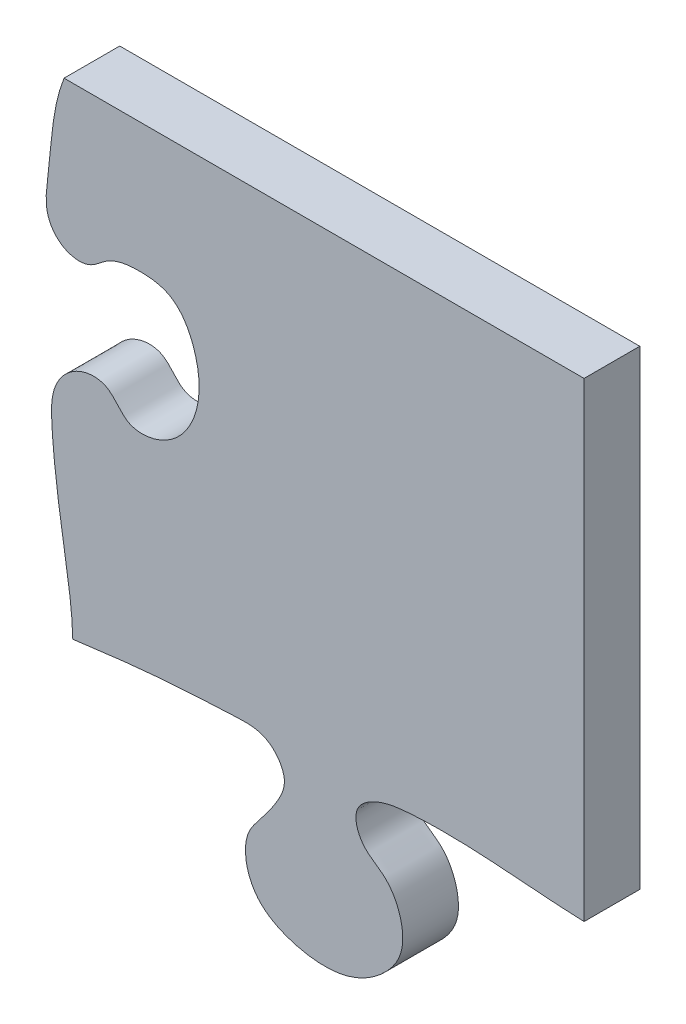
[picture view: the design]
ISO-10303-21;
HEADER;
FILE_DESCRIPTION(('STEP AP214'),'2;1');
FILE_NAME('part.step','',(''),(''),'','','');
FILE_SCHEMA(('AUTOMOTIVE_DESIGN { 1 0 10303 214 1 1 1 1 }'));
ENDSEC;
DATA;
#1=APPLICATION_CONTEXT('core data for automotive mechanical design processes');
#2=APPLICATION_PROTOCOL_DEFINITION('international standard','automotive_design',2000,#1);
#3=PRODUCT_CONTEXT('',#1,'mechanical');
#4=PRODUCT('Part','Part','',(#3));
#5=PRODUCT_RELATED_PRODUCT_CATEGORY('part','',(#4));
#6=PRODUCT_DEFINITION_FORMATION('','',#4);
#7=PRODUCT_DEFINITION_CONTEXT('part definition',#1,'design');
#8=PRODUCT_DEFINITION('design','',#6,#7);
#9=PRODUCT_DEFINITION_SHAPE('','',#8);
#10=(LENGTH_UNIT() NAMED_UNIT(*) SI_UNIT(.MILLI.,.METRE.));
#11=(NAMED_UNIT(*) PLANE_ANGLE_UNIT() SI_UNIT($,.RADIAN.));
#12=(NAMED_UNIT(*) SI_UNIT($,.STERADIAN.) SOLID_ANGLE_UNIT());
#13=UNCERTAINTY_MEASURE_WITH_UNIT(LENGTH_MEASURE(1.E-05),#10,'distance_accuracy_value','');
#14=(GEOMETRIC_REPRESENTATION_CONTEXT(3) GLOBAL_UNCERTAINTY_ASSIGNED_CONTEXT((#13)) GLOBAL_UNIT_ASSIGNED_CONTEXT((#10,
#11,#12)) REPRESENTATION_CONTEXT('',''));
#15=CARTESIAN_POINT('',(0.,0.,0.));
#16=DIRECTION('',(0.,0.,1.));
#17=DIRECTION('',(1.,0.,0.));
#18=AXIS2_PLACEMENT_3D('',#15,#16,#17);
#19=CARTESIAN_POINT('',(325.257058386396,356.,-0.00999999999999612));
#20=CARTESIAN_POINT('',(320.961162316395,345.029410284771,-0.00999999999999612));
#21=CARTESIAN_POINT('',(320.821863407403,330.111228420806,-0.00999999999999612));
#22=CARTESIAN_POINT('',(317.746642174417,310.708405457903,-0.00999999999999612));
#23=CARTESIAN_POINT('',(324.80874526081,302.068845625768,-0.00999999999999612));
#24=CARTESIAN_POINT('',(334.47949844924,301.092198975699,-0.00999999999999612));
#25=CARTESIAN_POINT('',(341.199385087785,308.405018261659,-0.00999999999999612));
#26=CARTESIAN_POINT('',(351.88918877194,310.104343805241,-0.00999999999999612));
#27=CARTESIAN_POINT('',(365.477229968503,308.551893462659,-0.00999999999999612));
#28=CARTESIAN_POINT('',(373.973100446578,293.452904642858,-0.00999999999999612));
#29=CARTESIAN_POINT('',(374.68177629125,275.222888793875,-0.00999999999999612));
#30=CARTESIAN_POINT('',(363.969524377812,260.217712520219,-0.00999999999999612));
#31=CARTESIAN_POINT('',(347.560929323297,258.00994019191,-0.00999999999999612));
#32=CARTESIAN_POINT('',(341.667769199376,269.318092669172,-0.00999999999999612));
#33=CARTESIAN_POINT('',(329.050646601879,268.591464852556,-0.00999999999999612));
#34=CARTESIAN_POINT('',(320.333215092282,258.695380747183,-0.00999999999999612));
#35=CARTESIAN_POINT('',(321.071783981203,237.536716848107,-0.00999999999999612));
#36=CARTESIAN_POINT('',(324.445641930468,214.63289279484,-0.00999999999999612));
#37=CARTESIAN_POINT('',(329.382935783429,185.164436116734,-0.00999999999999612));
#38=CARTESIAN_POINT('',(327.148862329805,151.381238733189,-0.00999999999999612));
#39=CARTESIAN_POINT('',(325.104399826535,122.782989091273,-0.00999999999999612));
#40=CARTESIAN_POINT('',(327.870971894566,95.9027200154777,-0.00999999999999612));
#41=CARTESIAN_POINT('',(342.142457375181,93.3383677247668,-0.00999999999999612));
#42=CARTESIAN_POINT('',(347.900573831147,101.981576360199,-0.00999999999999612));
#43=CARTESIAN_POINT('',(356.834615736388,107.765098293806,-0.00999999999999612));
#44=CARTESIAN_POINT('',(369.379527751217,108.600772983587,-0.00999999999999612));
#45=CARTESIAN_POINT('',(380.120269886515,95.9775166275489,-0.00999999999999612));
#46=CARTESIAN_POINT('',(380.578851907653,78.7451628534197,-0.00999999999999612));
#47=CARTESIAN_POINT('',(375.610818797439,61.7248962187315,-0.00999999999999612));
#48=CARTESIAN_POINT('',(363.715824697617,52.8157722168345,-0.00999999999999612));
#49=CARTESIAN_POINT('',(349.85984979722,55.1705340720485,-0.00999999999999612));
#50=CARTESIAN_POINT('',(346.945856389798,64.810819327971,-0.00999999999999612));
#51=CARTESIAN_POINT('',(338.689797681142,70.9897723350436,-0.00999999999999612));
#52=CARTESIAN_POINT('',(330.580353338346,62.4728514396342,-0.00999999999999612));
#53=CARTESIAN_POINT('',(328.928359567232,48.4436203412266,-0.00999999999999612));
#54=CARTESIAN_POINT('',(329.318852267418,30.6791591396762,-0.00999999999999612));
#55=CARTESIAN_POINT('',(330.266196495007,6.75725364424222,-0.00999999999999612));
#56=CARTESIAN_POINT('',(328.413221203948,-22.8156731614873,-0.00999999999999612));
#57=CARTESIAN_POINT('',(325.957403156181,-47.4645191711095,-0.00999999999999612));
#58=CARTESIAN_POINT('',(324.284943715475,-71.7282942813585,-0.00999999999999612));
#59=CARTESIAN_POINT('',(336.158184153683,-74.5800053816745,-0.00999999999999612));
#60=CARTESIAN_POINT('',(345.605596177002,-70.2479425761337,-0.00999999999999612));
#61=CARTESIAN_POINT('',(352.349142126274,-60.6528291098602,-0.00999999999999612));
#62=CARTESIAN_POINT('',(364.054661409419,-61.084248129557,-0.00999999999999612));
#63=CARTESIAN_POINT('',(376.894401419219,-65.7171784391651,-0.00999999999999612));
#64=CARTESIAN_POINT('',(383.833690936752,-81.7570856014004,-0.00999999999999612));
#65=CARTESIAN_POINT('',(380.385627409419,-99.5380411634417,-0.00999999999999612));
#66=CARTESIAN_POINT('',(369.163029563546,-108.064440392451,-0.00999999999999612));
#67=CARTESIAN_POINT('',(355.487733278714,-112.894616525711,-0.00999999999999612));
#68=CARTESIAN_POINT('',(345.56890588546,-106.804716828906,-0.00999999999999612));
#69=CARTESIAN_POINT('',(337.864154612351,-99.6791187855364,-0.00999999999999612));
#70=CARTESIAN_POINT('',(325.333875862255,-101.340144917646,-0.00999999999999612));
#71=CARTESIAN_POINT('',(326.442256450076,-127.027418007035,-0.00999999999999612));
#72=CARTESIAN_POINT('',(328.990782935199,-147.650339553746,-0.00999999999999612));
#73=CARTESIAN_POINT('',(331.889209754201,-175.720931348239,-0.00999999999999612));
#74=CARTESIAN_POINT('',(333.49389611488,-200.043501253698,-0.00999999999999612));
#75=CARTESIAN_POINT('',(333.062418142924,-222.75850264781,-0.00999999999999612));
#76=CARTESIAN_POINT('',(334.041200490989,-241.335918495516,-0.00999999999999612));
#77=CARTESIAN_POINT('',(324.292862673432,-248.82670983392,-0.00999999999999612));
#78=CARTESIAN_POINT('',(313.862264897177,-249.831348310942,-0.00999999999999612));
#79=CARTESIAN_POINT('',(308.055191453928,-242.821422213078,-0.00999999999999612));
#80=CARTESIAN_POINT('',(300.480173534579,-235.015509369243,-0.00999999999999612));
#81=CARTESIAN_POINT('',(285.021810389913,-234.387092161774,-0.00999999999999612));
#82=CARTESIAN_POINT('',(274.179995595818,-248.432983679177,-0.00999999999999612));
#83=CARTESIAN_POINT('',(270.871780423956,-265.971502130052,-0.00999999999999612));
#84=CARTESIAN_POINT('',(274.212392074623,-284.032454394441,-0.00999999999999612));
#85=CARTESIAN_POINT('',(287.225269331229,-295.05235393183,-0.00999999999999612));
#86=CARTESIAN_POINT('',(300.809811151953,-292.931473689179,-0.00999999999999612));
#87=CARTESIAN_POINT('',(307.364923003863,-284.321305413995,-0.00999999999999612));
#88=CARTESIAN_POINT('',(317.634904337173,-281.646810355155,-0.00999999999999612));
#89=CARTESIAN_POINT('',(335.194502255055,-286.515768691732,-0.00999999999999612));
#90=CARTESIAN_POINT('',(329.900008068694,-321.054322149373,-0.00999999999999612));
#91=CARTESIAN_POINT('',(330.939416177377,-339.80390498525,-0.00999999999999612));
#92=CARTESIAN_POINT('',(328.124742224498,-356.,-0.00999999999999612));
#93=B_SPLINE_CURVE_WITH_KNOTS('',3,(#19,#20,#21,#22,#23,#24,#25,#26,#27,#28,#29,#30,#31,#32,#33,
#34,#35,#36,#37,#38,#39,#40,#41,#42,#43,#44,#45,#46,#47,#48,#49,#50,#51,#52,#53,#54,#55,#56,#57,
#58,#59,#60,#61,#62,#63,#64,#65,#66,#67,#68,#69,#70,#71,#72,#73,#74,#75,#76,#77,#78,#79,#80,#81,
#82,#83,#84,#85,#86,#87,#88,#89,#90,#91,#92),.UNSPECIFIED.,.F.,.F.,(4,1,1,1,1,1,1,1,1,1,1,1,1,1,
1,1,1,1,1,1,1,1,1,1,1,1,1,1,1,1,1,1,1,1,1,1,1,1,1,1,1,1,1,1,1,1,1,1,1,1,1,1,1,1,1,1,1,1,1,1,1,1,
1,1,1,1,1,1,1,1,1,4),(0.,0.0294359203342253,0.0410015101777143,0.0482578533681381,
0.056156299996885,0.0628725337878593,0.0726761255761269,0.0834491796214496,0.0961628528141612,
0.113582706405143,0.1292026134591,0.140393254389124,0.149299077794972,0.1578234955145,
0.168702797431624,0.18034067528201,0.211171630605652,0.230177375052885,0.258218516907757,
0.297936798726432,0.310855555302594,0.319545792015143,0.327782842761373,0.335750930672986,
0.347377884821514,0.35651553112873,0.375682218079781,0.389966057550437,0.401463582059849,
0.411615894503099,0.420595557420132,0.426581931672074,0.43417370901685,0.444880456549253,
0.464136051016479,0.480140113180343,0.507902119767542,0.539252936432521,0.552990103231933,
0.558383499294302,0.567729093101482,0.578921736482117,0.586248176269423,0.596305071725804,
0.613504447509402,0.626237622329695,0.64117705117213,0.647978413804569,0.662971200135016,
0.667795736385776,0.675224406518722,0.689293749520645,0.721613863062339,0.73643728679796,
0.762019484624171,0.785031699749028,0.797726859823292,0.806664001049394,0.814473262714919,
0.822386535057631,0.828765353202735,0.842978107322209,0.855573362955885,0.871677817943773,
0.889062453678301,0.900888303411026,0.912516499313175,0.920249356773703,0.928039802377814,
0.939164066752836,0.961164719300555,1.),.UNSPECIFIED.);
#94=DIRECTION('',(0.,0.,1.));
#95=VECTOR('',#94,1.);
#96=SURFACE_OF_LINEAR_EXTRUSION('',#93,#95);
#97=DIRECTION('',(0.,0.,1.));
#98=VECTOR('',#97,1.);
#99=CARTESIAN_POINT('',(328.393413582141,183.083092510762,-0.00999999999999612));
#100=LINE('',#99,#98);
#101=CARTESIAN_POINT('',(328.393413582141,183.083092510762,20.));
#102=VERTEX_POINT('',#101);
#103=CARTESIAN_POINT('',(328.393413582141,183.083092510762,0.));
#104=VERTEX_POINT('',#103);
#105=EDGE_CURVE('E95',#102,#104,#100,.F.);
#106=ORIENTED_EDGE('',*,*,#105,.F.);
#107=CARTESIAN_POINT('',(325.257058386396,356.,20.));
#108=CARTESIAN_POINT('',(320.961162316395,345.029410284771,20.));
#109=CARTESIAN_POINT('',(320.821863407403,330.111228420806,20.));
#110=CARTESIAN_POINT('',(317.746642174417,310.708405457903,20.));
#111=CARTESIAN_POINT('',(324.80874526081,302.068845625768,20.));
#112=CARTESIAN_POINT('',(334.47949844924,301.092198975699,20.));
#113=CARTESIAN_POINT('',(341.199385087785,308.405018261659,20.));
#114=CARTESIAN_POINT('',(351.88918877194,310.104343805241,20.));
#115=CARTESIAN_POINT('',(365.477229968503,308.551893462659,20.));
#116=CARTESIAN_POINT('',(373.973100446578,293.452904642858,20.));
#117=CARTESIAN_POINT('',(374.68177629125,275.222888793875,20.));
#118=CARTESIAN_POINT('',(363.969524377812,260.217712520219,20.));
#119=CARTESIAN_POINT('',(347.560929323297,258.00994019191,20.));
#120=CARTESIAN_POINT('',(341.667769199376,269.318092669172,20.));
#121=CARTESIAN_POINT('',(329.050646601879,268.591464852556,20.));
#122=CARTESIAN_POINT('',(320.333215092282,258.695380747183,20.));
#123=CARTESIAN_POINT('',(321.071783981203,237.536716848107,20.));
#124=CARTESIAN_POINT('',(324.445641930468,214.63289279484,20.));
#125=CARTESIAN_POINT('',(329.382935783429,185.164436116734,20.));
#126=CARTESIAN_POINT('',(327.148862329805,151.381238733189,20.));
#127=CARTESIAN_POINT('',(325.104399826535,122.782989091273,20.));
#128=CARTESIAN_POINT('',(327.870971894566,95.9027200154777,20.));
#129=CARTESIAN_POINT('',(342.142457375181,93.3383677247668,20.));
#130=CARTESIAN_POINT('',(347.900573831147,101.981576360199,20.));
#131=CARTESIAN_POINT('',(356.834615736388,107.765098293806,20.));
#132=CARTESIAN_POINT('',(369.379527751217,108.600772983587,20.));
#133=CARTESIAN_POINT('',(380.120269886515,95.9775166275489,20.));
#134=CARTESIAN_POINT('',(380.578851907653,78.7451628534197,20.));
#135=CARTESIAN_POINT('',(375.610818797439,61.7248962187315,20.));
#136=CARTESIAN_POINT('',(363.715824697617,52.8157722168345,20.));
#137=CARTESIAN_POINT('',(349.85984979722,55.1705340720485,20.));
#138=CARTESIAN_POINT('',(346.945856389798,64.810819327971,20.));
#139=CARTESIAN_POINT('',(338.689797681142,70.9897723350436,20.));
#140=CARTESIAN_POINT('',(330.580353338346,62.4728514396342,20.));
#141=CARTESIAN_POINT('',(328.928359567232,48.4436203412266,20.));
#142=CARTESIAN_POINT('',(329.318852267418,30.6791591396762,20.));
#143=CARTESIAN_POINT('',(330.266196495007,6.75725364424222,20.));
#144=CARTESIAN_POINT('',(328.413221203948,-22.8156731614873,20.));
#145=CARTESIAN_POINT('',(325.957403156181,-47.4645191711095,20.));
#146=CARTESIAN_POINT('',(324.284943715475,-71.7282942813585,20.));
#147=CARTESIAN_POINT('',(336.158184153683,-74.5800053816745,20.));
#148=CARTESIAN_POINT('',(345.605596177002,-70.2479425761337,20.));
#149=CARTESIAN_POINT('',(352.349142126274,-60.6528291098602,20.));
#150=CARTESIAN_POINT('',(364.054661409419,-61.084248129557,20.));
#151=CARTESIAN_POINT('',(376.894401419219,-65.7171784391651,20.));
#152=CARTESIAN_POINT('',(383.833690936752,-81.7570856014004,20.));
#153=CARTESIAN_POINT('',(380.385627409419,-99.5380411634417,20.));
#154=CARTESIAN_POINT('',(369.163029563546,-108.064440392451,20.));
#155=CARTESIAN_POINT('',(355.487733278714,-112.894616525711,20.));
#156=CARTESIAN_POINT('',(345.56890588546,-106.804716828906,20.));
#157=CARTESIAN_POINT('',(337.864154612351,-99.6791187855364,20.));
#158=CARTESIAN_POINT('',(325.333875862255,-101.340144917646,20.));
#159=CARTESIAN_POINT('',(326.442256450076,-127.027418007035,20.));
#160=CARTESIAN_POINT('',(328.990782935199,-147.650339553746,20.));
#161=CARTESIAN_POINT('',(331.889209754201,-175.720931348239,20.));
#162=CARTESIAN_POINT('',(333.49389611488,-200.043501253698,20.));
#163=CARTESIAN_POINT('',(333.062418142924,-222.75850264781,20.));
#164=CARTESIAN_POINT('',(334.041200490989,-241.335918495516,20.));
#165=CARTESIAN_POINT('',(324.292862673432,-248.82670983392,20.));
#166=CARTESIAN_POINT('',(313.862264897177,-249.831348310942,20.));
#167=CARTESIAN_POINT('',(308.055191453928,-242.821422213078,20.));
#168=CARTESIAN_POINT('',(300.480173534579,-235.015509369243,20.));
#169=CARTESIAN_POINT('',(285.021810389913,-234.387092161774,20.));
#170=CARTESIAN_POINT('',(274.179995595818,-248.432983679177,20.));
#171=CARTESIAN_POINT('',(270.871780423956,-265.971502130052,20.));
#172=CARTESIAN_POINT('',(274.212392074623,-284.032454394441,20.));
#173=CARTESIAN_POINT('',(287.225269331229,-295.05235393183,20.));
#174=CARTESIAN_POINT('',(300.809811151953,-292.931473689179,20.));
#175=CARTESIAN_POINT('',(307.364923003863,-284.321305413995,20.));
#176=CARTESIAN_POINT('',(317.634904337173,-281.646810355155,20.));
#177=CARTESIAN_POINT('',(335.194502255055,-286.515768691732,20.));
#178=CARTESIAN_POINT('',(329.900008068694,-321.054322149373,20.));
#179=CARTESIAN_POINT('',(330.939416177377,-339.80390498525,20.));
#180=CARTESIAN_POINT('',(328.124742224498,-356.,20.));
#181=B_SPLINE_CURVE_WITH_KNOTS('',3,(#107,#108,#109,#110,#111,#112,#113,#114,#115,#116,#117,
#118,#119,#120,#121,#122,#123,#124,#125,#126,#127,#128,#129,#130,#131,#132,#133,#134,#135,#136,
#137,#138,#139,#140,#141,#142,#143,#144,#145,#146,#147,#148,#149,#150,#151,#152,#153,#154,#155,
#156,#157,#158,#159,#160,#161,#162,#163,#164,#165,#166,#167,#168,#169,#170,#171,#172,#173,#174,
#175,#176,#177,#178,#179,#180),.UNSPECIFIED.,.F.,.F.,(4,1,1,1,1,1,1,1,1,1,1,1,1,1,1,1,1,1,1,1,1,
1,1,1,1,1,1,1,1,1,1,1,1,1,1,1,1,1,1,1,1,1,1,1,1,1,1,1,1,1,1,1,1,1,1,1,1,1,1,1,1,1,1,1,1,1,1,1,1,
1,1,4),(0.,0.0294359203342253,0.0410015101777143,0.0482578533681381,0.056156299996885,
0.0628725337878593,0.0726761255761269,0.0834491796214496,0.0961628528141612,0.113582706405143,
0.1292026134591,0.140393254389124,0.149299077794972,0.1578234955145,0.168702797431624,
0.18034067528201,0.211171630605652,0.230177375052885,0.258218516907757,0.297936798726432,
0.310855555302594,0.319545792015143,0.327782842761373,0.335750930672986,0.347377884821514,
0.35651553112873,0.375682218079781,0.389966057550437,0.401463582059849,0.411615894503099,
0.420595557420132,0.426581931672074,0.43417370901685,0.444880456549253,0.464136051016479,
0.480140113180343,0.507902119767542,0.539252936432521,0.552990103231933,0.558383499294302,
0.567729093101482,0.578921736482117,0.586248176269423,0.596305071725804,0.613504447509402,
0.626237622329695,0.64117705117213,0.647978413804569,0.662971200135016,0.667795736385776,
0.675224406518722,0.689293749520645,0.721613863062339,0.73643728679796,0.762019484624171,
0.785031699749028,0.797726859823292,0.806664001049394,0.814473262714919,0.822386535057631,
0.828765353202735,0.842978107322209,0.855573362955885,0.871677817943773,0.889062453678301,
0.900888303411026,0.912516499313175,0.920249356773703,0.928039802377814,0.939164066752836,
0.961164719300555,1.),.UNSPECIFIED.);
#182=CARTESIAN_POINT('',(325.257058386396,356.,20.));
#183=VERTEX_POINT('',#182);
#184=EDGE_CURVE('E94',#183,#102,#181,.T.);
#185=ORIENTED_EDGE('',*,*,#184,.F.);
#186=DIRECTION('',(0.,0.,1.));
#187=VECTOR('',#186,1.);
#188=CARTESIAN_POINT('',(325.257058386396,356.,-0.00999999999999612));
#189=LINE('',#188,#187);
#190=CARTESIAN_POINT('',(325.257058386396,356.,0.));
#191=VERTEX_POINT('',#190);
#192=EDGE_CURVE('E82',#183,#191,#189,.F.);
#193=ORIENTED_EDGE('',*,*,#192,.T.);
#194=CARTESIAN_POINT('',(325.257058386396,356.,0.));
#195=CARTESIAN_POINT('',(320.961162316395,345.029410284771,0.));
#196=CARTESIAN_POINT('',(320.821863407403,330.111228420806,0.));
#197=CARTESIAN_POINT('',(317.746642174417,310.708405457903,0.));
#198=CARTESIAN_POINT('',(324.80874526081,302.068845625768,0.));
#199=CARTESIAN_POINT('',(334.47949844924,301.092198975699,0.));
#200=CARTESIAN_POINT('',(341.199385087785,308.405018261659,0.));
#201=CARTESIAN_POINT('',(351.88918877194,310.104343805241,0.));
#202=CARTESIAN_POINT('',(365.477229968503,308.551893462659,0.));
#203=CARTESIAN_POINT('',(373.973100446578,293.452904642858,0.));
#204=CARTESIAN_POINT('',(374.68177629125,275.222888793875,0.));
#205=CARTESIAN_POINT('',(363.969524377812,260.217712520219,0.));
#206=CARTESIAN_POINT('',(347.560929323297,258.00994019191,0.));
#207=CARTESIAN_POINT('',(341.667769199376,269.318092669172,0.));
#208=CARTESIAN_POINT('',(329.050646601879,268.591464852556,0.));
#209=CARTESIAN_POINT('',(320.333215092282,258.695380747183,0.));
#210=CARTESIAN_POINT('',(321.071783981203,237.536716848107,0.));
#211=CARTESIAN_POINT('',(324.445641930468,214.63289279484,0.));
#212=CARTESIAN_POINT('',(329.382935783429,185.164436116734,0.));
#213=CARTESIAN_POINT('',(327.148862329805,151.381238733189,0.));
#214=CARTESIAN_POINT('',(325.104399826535,122.782989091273,0.));
#215=CARTESIAN_POINT('',(327.870971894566,95.9027200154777,0.));
#216=CARTESIAN_POINT('',(342.142457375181,93.3383677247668,0.));
#217=CARTESIAN_POINT('',(347.900573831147,101.981576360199,0.));
#218=CARTESIAN_POINT('',(356.834615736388,107.765098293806,0.));
#219=CARTESIAN_POINT('',(369.379527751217,108.600772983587,0.));
#220=CARTESIAN_POINT('',(380.120269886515,95.9775166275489,0.));
#221=CARTESIAN_POINT('',(380.578851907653,78.7451628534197,0.));
#222=CARTESIAN_POINT('',(375.610818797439,61.7248962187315,0.));
#223=CARTESIAN_POINT('',(363.715824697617,52.8157722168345,0.));
#224=CARTESIAN_POINT('',(349.85984979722,55.1705340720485,0.));
#225=CARTESIAN_POINT('',(346.945856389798,64.810819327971,0.));
#226=CARTESIAN_POINT('',(338.689797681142,70.9897723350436,0.));
#227=CARTESIAN_POINT('',(330.580353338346,62.4728514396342,0.));
#228=CARTESIAN_POINT('',(328.928359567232,48.4436203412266,0.));
#229=CARTESIAN_POINT('',(329.318852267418,30.6791591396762,0.));
#230=CARTESIAN_POINT('',(330.266196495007,6.75725364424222,0.));
#231=CARTESIAN_POINT('',(328.413221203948,-22.8156731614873,0.));
#232=CARTESIAN_POINT('',(325.957403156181,-47.4645191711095,0.));
#233=CARTESIAN_POINT('',(324.284943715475,-71.7282942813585,0.));
#234=CARTESIAN_POINT('',(336.158184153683,-74.5800053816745,0.));
#235=CARTESIAN_POINT('',(345.605596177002,-70.2479425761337,0.));
#236=CARTESIAN_POINT('',(352.349142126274,-60.6528291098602,0.));
#237=CARTESIAN_POINT('',(364.054661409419,-61.084248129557,0.));
#238=CARTESIAN_POINT('',(376.894401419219,-65.7171784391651,0.));
#239=CARTESIAN_POINT('',(383.833690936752,-81.7570856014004,0.));
#240=CARTESIAN_POINT('',(380.385627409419,-99.5380411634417,0.));
#241=CARTESIAN_POINT('',(369.163029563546,-108.064440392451,0.));
#242=CARTESIAN_POINT('',(355.487733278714,-112.894616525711,0.));
#243=CARTESIAN_POINT('',(345.56890588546,-106.804716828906,0.));
#244=CARTESIAN_POINT('',(337.864154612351,-99.6791187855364,0.));
#245=CARTESIAN_POINT('',(325.333875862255,-101.340144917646,0.));
#246=CARTESIAN_POINT('',(326.442256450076,-127.027418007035,0.));
#247=CARTESIAN_POINT('',(328.990782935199,-147.650339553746,0.));
#248=CARTESIAN_POINT('',(331.889209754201,-175.720931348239,0.));
#249=CARTESIAN_POINT('',(333.49389611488,-200.043501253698,0.));
#250=CARTESIAN_POINT('',(333.062418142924,-222.75850264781,0.));
#251=CARTESIAN_POINT('',(334.041200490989,-241.335918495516,0.));
#252=CARTESIAN_POINT('',(324.292862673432,-248.82670983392,0.));
#253=CARTESIAN_POINT('',(313.862264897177,-249.831348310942,0.));
#254=CARTESIAN_POINT('',(308.055191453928,-242.821422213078,0.));
#255=CARTESIAN_POINT('',(300.480173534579,-235.015509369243,0.));
#256=CARTESIAN_POINT('',(285.021810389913,-234.387092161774,0.));
#257=CARTESIAN_POINT('',(274.179995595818,-248.432983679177,0.));
#258=CARTESIAN_POINT('',(270.871780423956,-265.971502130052,0.));
#259=CARTESIAN_POINT('',(274.212392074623,-284.032454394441,0.));
#260=CARTESIAN_POINT('',(287.225269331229,-295.05235393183,0.));
#261=CARTESIAN_POINT('',(300.809811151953,-292.931473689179,0.));
#262=CARTESIAN_POINT('',(307.364923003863,-284.321305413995,0.));
#263=CARTESIAN_POINT('',(317.634904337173,-281.646810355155,0.));
#264=CARTESIAN_POINT('',(335.194502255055,-286.515768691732,0.));
#265=CARTESIAN_POINT('',(329.900008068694,-321.054322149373,0.));
#266=CARTESIAN_POINT('',(330.939416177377,-339.80390498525,0.));
#267=CARTESIAN_POINT('',(328.124742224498,-356.,0.));
#268=B_SPLINE_CURVE_WITH_KNOTS('',3,(#194,#195,#196,#197,#198,#199,#200,#201,#202,#203,#204,
#205,#206,#207,#208,#209,#210,#211,#212,#213,#214,#215,#216,#217,#218,#219,#220,#221,#222,#223,
#224,#225,#226,#227,#228,#229,#230,#231,#232,#233,#234,#235,#236,#237,#238,#239,#240,#241,#242,
#243,#244,#245,#246,#247,#248,#249,#250,#251,#252,#253,#254,#255,#256,#257,#258,#259,#260,#261,
#262,#263,#264,#265,#266,#267),.UNSPECIFIED.,.F.,.F.,(4,1,1,1,1,1,1,1,1,1,1,1,1,1,1,1,1,1,1,1,1,
1,1,1,1,1,1,1,1,1,1,1,1,1,1,1,1,1,1,1,1,1,1,1,1,1,1,1,1,1,1,1,1,1,1,1,1,1,1,1,1,1,1,1,1,1,1,1,1,
1,1,4),(0.,0.0294359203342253,0.0410015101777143,0.0482578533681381,0.056156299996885,
0.0628725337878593,0.0726761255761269,0.0834491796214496,0.0961628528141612,0.113582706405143,
0.1292026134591,0.140393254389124,0.149299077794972,0.1578234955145,0.168702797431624,
0.18034067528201,0.211171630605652,0.230177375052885,0.258218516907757,0.297936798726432,
0.310855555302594,0.319545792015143,0.327782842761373,0.335750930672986,0.347377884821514,
0.35651553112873,0.375682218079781,0.389966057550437,0.401463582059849,0.411615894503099,
0.420595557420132,0.426581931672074,0.43417370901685,0.444880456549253,0.464136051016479,
0.480140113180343,0.507902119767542,0.539252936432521,0.552990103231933,0.558383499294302,
0.567729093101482,0.578921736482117,0.586248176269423,0.596305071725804,0.613504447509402,
0.626237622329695,0.64117705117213,0.647978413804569,0.662971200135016,0.667795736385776,
0.675224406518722,0.689293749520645,0.721613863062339,0.73643728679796,0.762019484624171,
0.785031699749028,0.797726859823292,0.806664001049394,0.814473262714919,0.822386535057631,
0.828765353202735,0.842978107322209,0.855573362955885,0.871677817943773,0.889062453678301,
0.900888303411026,0.912516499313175,0.920249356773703,0.928039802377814,0.939164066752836,
0.961164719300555,1.),.UNSPECIFIED.);
#269=EDGE_CURVE('E93',#191,#104,#268,.T.);
#270=ORIENTED_EDGE('',*,*,#269,.T.);
#271=EDGE_LOOP('',(#106,#185,#193,#270));
#272=FACE_BOUND('',#271,.T.);
#273=ADVANCED_FACE('F34',(#272),#96,.T.);
#274=CARTESIAN_POINT('',(512.,-356.,20.));
#275=DIRECTION('',(-1.,0.,0.));
#276=DIRECTION('',(0.,0.,1.));
#277=AXIS2_PLACEMENT_3D('',#274,#275,#276);
#278=PLANE('',#277);
#279=DIRECTION('',(0.,0.,1.));
#280=VECTOR('',#279,1.);
#281=CARTESIAN_POINT('',(512.,187.076538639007,-0.00999999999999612));
#282=LINE('',#281,#280);
#283=CARTESIAN_POINT('',(512.,187.076538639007,0.));
#284=VERTEX_POINT('',#283);
#285=CARTESIAN_POINT('',(512.,187.076538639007,20.));
#286=VERTEX_POINT('',#285);
#287=EDGE_CURVE('E45',#284,#286,#282,.T.);
#288=ORIENTED_EDGE('',*,*,#287,.F.);
#289=DIRECTION('',(0.,1.,0.));
#290=VECTOR('',#289,1.);
#291=CARTESIAN_POINT('',(512.,-356.,0.));
#292=LINE('',#291,#290);
#293=CARTESIAN_POINT('',(512.,356.,0.));
#294=VERTEX_POINT('',#293);
#295=EDGE_CURVE('E89',#284,#294,#292,.T.);
#296=ORIENTED_EDGE('',*,*,#295,.T.);
#297=DIRECTION('',(0.,0.,-1.));
#298=VECTOR('',#297,1.);
#299=CARTESIAN_POINT('',(512.,356.,20.));
#300=LINE('',#299,#298);
#301=CARTESIAN_POINT('',(512.,356.,20.));
#302=VERTEX_POINT('',#301);
#303=EDGE_CURVE('E85',#302,#294,#300,.T.);
#304=ORIENTED_EDGE('',*,*,#303,.F.);
#305=DIRECTION('',(0.,1.,0.));
#306=VECTOR('',#305,1.);
#307=CARTESIAN_POINT('',(512.,-356.,20.));
#308=LINE('',#307,#306);
#309=EDGE_CURVE('E88',#286,#302,#308,.T.);
#310=ORIENTED_EDGE('',*,*,#309,.F.);
#311=EDGE_LOOP('',(#288,#296,#304,#310));
#312=FACE_BOUND('',#311,.T.);
#313=ADVANCED_FACE('F126',(#312),#278,.F.);
#314=CARTESIAN_POINT('',(-346.614016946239,177.25293926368,-0.00999999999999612));
#315=CARTESIAN_POINT('',(-342.258832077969,176.736071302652,-0.00999999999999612));
#316=CARTESIAN_POINT('',(-334.630281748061,175.39162503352,-0.00999999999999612));
#317=CARTESIAN_POINT('',(-322.207300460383,172.127174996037,-0.00999999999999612));
#318=CARTESIAN_POINT('',(-310.217613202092,171.698509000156,-0.00999999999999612));
#319=CARTESIAN_POINT('',(-298.545158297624,170.093475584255,-0.00999999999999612));
#320=CARTESIAN_POINT('',(-292.347039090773,176.459047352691,-0.00999999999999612));
#321=CARTESIAN_POINT('',(-291.182342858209,183.091468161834,-0.00999999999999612));
#322=CARTESIAN_POINT('',(-293.102487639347,190.125199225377,-0.00999999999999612));
#323=CARTESIAN_POINT('',(-298.136160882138,196.044180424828,-0.00999999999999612));
#324=CARTESIAN_POINT('',(-298.244257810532,205.192484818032,-0.00999999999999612));
#325=CARTESIAN_POINT('',(-295.736411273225,216.192904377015,-0.00999999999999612));
#326=CARTESIAN_POINT('',(-284.569633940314,223.791693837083,-0.00999999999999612));
#327=CARTESIAN_POINT('',(-272.468924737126,223.790848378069,-0.00999999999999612));
#328=CARTESIAN_POINT('',(-261.822732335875,221.83725535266,-0.00999999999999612));
#329=CARTESIAN_POINT('',(-253.508338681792,215.027886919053,-0.00999999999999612));
#330=CARTESIAN_POINT('',(-252.519805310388,205.637670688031,-0.00999999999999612));
#331=CARTESIAN_POINT('',(-253.401239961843,197.704569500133,-0.00999999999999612));
#332=CARTESIAN_POINT('',(-258.083644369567,192.838143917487,-0.00999999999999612));
#333=CARTESIAN_POINT('',(-261.982487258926,187.038073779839,-0.00999999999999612));
#334=CARTESIAN_POINT('',(-259.723590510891,179.281829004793,-0.00999999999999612));
#335=CARTESIAN_POINT('',(-251.85351516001,173.410794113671,-0.00999999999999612));
#336=CARTESIAN_POINT('',(-238.882669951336,174.366863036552,-0.00999999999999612));
#337=CARTESIAN_POINT('',(-223.106306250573,172.916178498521,-0.00999999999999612));
#338=CARTESIAN_POINT('',(-206.446351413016,177.519441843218,-0.00999999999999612));
#339=CARTESIAN_POINT('',(-190.340722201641,179.324744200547,-0.00999999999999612));
#340=CARTESIAN_POINT('',(-176.104340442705,182.349104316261,-0.00999999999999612));
#341=CARTESIAN_POINT('',(-163.084589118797,183.756571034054,-0.00999999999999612));
#342=CARTESIAN_POINT('',(-148.792468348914,185.344350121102,-0.00999999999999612));
#343=CARTESIAN_POINT('',(-133.845084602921,186.050988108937,-0.00999999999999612));
#344=CARTESIAN_POINT('',(-120.037545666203,188.092783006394,-0.00999999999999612));
#345=CARTESIAN_POINT('',(-111.803418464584,182.78300514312,-0.00999999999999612));
#346=CARTESIAN_POINT('',(-111.114798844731,176.517531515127,-0.00999999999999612));
#347=CARTESIAN_POINT('',(-112.872183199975,170.302712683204,-0.00999999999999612));
#348=CARTESIAN_POINT('',(-117.51230307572,165.00187907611,-0.00999999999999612));
#349=CARTESIAN_POINT('',(-123.315488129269,161.011850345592,-0.00999999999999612));
#350=CARTESIAN_POINT('',(-125.896005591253,153.215627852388,-0.00999999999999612));
#351=CARTESIAN_POINT('',(-123.567507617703,140.925485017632,-0.00999999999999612));
#352=CARTESIAN_POINT('',(-111.885113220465,130.083380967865,-0.00999999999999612));
#353=CARTESIAN_POINT('',(-95.9373878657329,129.405548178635,-0.00999999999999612));
#354=CARTESIAN_POINT('',(-84.8374492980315,134.872773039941,-0.00999999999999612));
#355=CARTESIAN_POINT('',(-75.3086923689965,142.091043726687,-0.00999999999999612));
#356=CARTESIAN_POINT('',(-72.69488446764,152.131847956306,-0.00999999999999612));
#357=CARTESIAN_POINT('',(-71.682221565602,162.525177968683,-0.00999999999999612));
#358=CARTESIAN_POINT('',(-78.7549399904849,168.95980357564,-0.00999999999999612));
#359=CARTESIAN_POINT('',(-85.5168727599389,177.593918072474,-0.00999999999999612));
#360=CARTESIAN_POINT('',(-75.9954684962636,187.469530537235,-0.00999999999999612));
#361=CARTESIAN_POINT('',(-67.465440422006,186.249883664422,-0.00999999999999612));
#362=CARTESIAN_POINT('',(-58.2366685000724,186.245624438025,-0.00999999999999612));
#363=CARTESIAN_POINT('',(-48.8132938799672,186.807289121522,-0.00999999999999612));
#364=CARTESIAN_POINT('',(-33.2056867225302,186.136328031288,-0.00999999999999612));
#365=CARTESIAN_POINT('',(-12.537524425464,187.517682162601,-0.00999999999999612));
#366=CARTESIAN_POINT('',(11.5103154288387,188.924750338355,-0.00999999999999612));
#367=CARTESIAN_POINT('',(30.1849441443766,189.011039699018,-0.00999999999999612));
#368=CARTESIAN_POINT('',(43.274525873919,189.889723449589,-0.00999999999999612));
#369=CARTESIAN_POINT('',(48.0164168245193,183.93060080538,-0.00999999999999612));
#370=CARTESIAN_POINT('',(50.5774279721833,176.61864331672,-0.00999999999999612));
#371=CARTESIAN_POINT('',(46.6862848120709,168.851584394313,-0.00999999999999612));
#372=CARTESIAN_POINT('',(40.9041593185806,162.199492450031,-0.00999999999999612));
#373=CARTESIAN_POINT('',(40.64695704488,152.479125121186,-0.00999999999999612));
#374=CARTESIAN_POINT('',(45.9753197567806,142.379370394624,-0.00999999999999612));
#375=CARTESIAN_POINT('',(57.8656738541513,133.606511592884,-0.00999999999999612));
#376=CARTESIAN_POINT('',(73.1959810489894,132.323999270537,-0.00999999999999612));
#377=CARTESIAN_POINT('',(85.4204286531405,138.139947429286,-0.00999999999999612));
#378=CARTESIAN_POINT('',(91.293500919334,147.271529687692,-0.00999999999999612));
#379=CARTESIAN_POINT('',(92.5730258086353,158.4481335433,-0.00999999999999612));
#380=CARTESIAN_POINT('',(85.6844462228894,167.316232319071,-0.00999999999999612));
#381=CARTESIAN_POINT('',(79.232667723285,177.018523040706,-0.00999999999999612));
#382=CARTESIAN_POINT('',(84.0194361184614,186.167590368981,-0.00999999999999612));
#383=CARTESIAN_POINT('',(92.1790662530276,191.943337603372,-0.00999999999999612));
#384=CARTESIAN_POINT('',(105.569170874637,191.361104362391,-0.00999999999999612));
#385=CARTESIAN_POINT('',(122.280046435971,190.653524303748,-0.00999999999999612));
#386=CARTESIAN_POINT('',(140.914243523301,189.654608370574,-0.00999999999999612));
#387=CARTESIAN_POINT('',(158.454428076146,188.894575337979,-0.00999999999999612));
#388=CARTESIAN_POINT('',(174.308585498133,185.327210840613,-0.00999999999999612));
#389=CARTESIAN_POINT('',(190.189391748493,182.787078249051,-0.00999999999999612));
#390=CARTESIAN_POINT('',(205.520873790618,180.707698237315,-0.00999999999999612));
#391=CARTESIAN_POINT('',(219.985633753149,180.329082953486,-0.00999999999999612));
#392=CARTESIAN_POINT('',(230.995486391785,184.637134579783,-0.00999999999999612));
#393=CARTESIAN_POINT('',(236.389631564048,193.96740057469,-0.00999999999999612));
#394=CARTESIAN_POINT('',(234.339311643,204.099038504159,-0.00999999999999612));
#395=CARTESIAN_POINT('',(225.306966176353,209.962524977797,-0.00999999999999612));
#396=CARTESIAN_POINT('',(217.656290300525,220.555550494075,-0.00999999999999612));
#397=CARTESIAN_POINT('',(221.434208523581,234.75430994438,-0.00999999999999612));
#398=CARTESIAN_POINT('',(231.413638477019,244.865362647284,-0.00999999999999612));
#399=CARTESIAN_POINT('',(243.993390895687,246.564716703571,-0.00999999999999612));
#400=CARTESIAN_POINT('',(256.397546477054,246.182971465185,-0.00999999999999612));
#401=CARTESIAN_POINT('',(266.945867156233,239.095387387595,-0.00999999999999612));
#402=CARTESIAN_POINT('',(270.91124628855,228.240855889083,-0.00999999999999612));
#403=CARTESIAN_POINT('',(271.900091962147,218.911541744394,-0.00999999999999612));
#404=CARTESIAN_POINT('',(269.383381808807,210.410798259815,-0.00999999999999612));
#405=CARTESIAN_POINT('',(262.973596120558,206.796374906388,-0.00999999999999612));
#406=CARTESIAN_POINT('',(257.405320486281,203.494234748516,-0.00999999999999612));
#407=CARTESIAN_POINT('',(254.366674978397,197.840465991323,-0.00999999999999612));
#408=CARTESIAN_POINT('',(253.039843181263,191.819395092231,-0.00999999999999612));
#409=CARTESIAN_POINT('',(256.984226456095,185.562553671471,-0.00999999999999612));
#410=CARTESIAN_POINT('',(265.893667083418,181.084683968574,-0.00999999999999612));
#411=CARTESIAN_POINT('',(279.937105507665,178.460081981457,-0.00999999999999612));
#412=CARTESIAN_POINT('',(295.857197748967,180.090608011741,-0.00999999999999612));
#413=CARTESIAN_POINT('',(312.651995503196,181.441283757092,-0.00999999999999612));
#414=CARTESIAN_POINT('',(328.737066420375,183.00567531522,-0.00999999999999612));
#415=CARTESIAN_POINT('',(346.881588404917,185.540652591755,-0.00999999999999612));
#416=CARTESIAN_POINT('',(366.113245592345,187.229469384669,-0.00999999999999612));
#417=CARTESIAN_POINT('',(383.091271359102,188.04749837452,-0.00999999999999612));
#418=CARTESIAN_POINT('',(396.458935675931,188.664584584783,-0.00999999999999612));
#419=CARTESIAN_POINT('',(402.675626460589,183.140178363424,-0.00999999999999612));
#420=CARTESIAN_POINT('',(405.39161009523,176.05770043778,-0.00999999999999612));
#421=CARTESIAN_POINT('',(401.505929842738,168.451181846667,-0.00999999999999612));
#422=CARTESIAN_POINT('',(396.461764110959,161.551049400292,-0.00999999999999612));
#423=CARTESIAN_POINT('',(390.92163398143,155.05556636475,-0.00999999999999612));
#424=CARTESIAN_POINT('',(389.792834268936,145.579550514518,-0.00999999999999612));
#425=CARTESIAN_POINT('',(394.021335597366,134.09834255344,-0.00999999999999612));
#426=CARTESIAN_POINT('',(409.134243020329,126.516671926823,-0.00999999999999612));
#427=CARTESIAN_POINT('',(426.048788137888,125.694722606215,-0.00999999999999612));
#428=CARTESIAN_POINT('',(439.554422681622,133.604839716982,-0.00999999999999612));
#429=CARTESIAN_POINT('',(447.862161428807,144.021049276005,-0.00999999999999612));
#430=CARTESIAN_POINT('',(446.55931165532,156.434302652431,-0.00999999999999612));
#431=CARTESIAN_POINT('',(440.954543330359,165.911582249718,-0.00999999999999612));
#432=CARTESIAN_POINT('',(431.825738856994,170.072611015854,-0.00999999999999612));
#433=CARTESIAN_POINT('',(428.260955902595,181.518173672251,-0.00999999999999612));
#434=CARTESIAN_POINT('',(438.266894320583,188.341732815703,-0.00999999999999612));
#435=CARTESIAN_POINT('',(452.042143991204,189.873820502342,-0.00999999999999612));
#436=CARTESIAN_POINT('',(477.265793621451,189.952490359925,-0.00999999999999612));
#437=CARTESIAN_POINT('',(497.972189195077,187.546114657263,-0.00999999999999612));
#438=CARTESIAN_POINT('',(512.,187.076538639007,-0.00999999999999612));
#439=B_SPLINE_CURVE_WITH_KNOTS('',3,(#314,#315,#316,#317,#318,#319,#320,#321,#322,#323,#324,
#325,#326,#327,#328,#329,#330,#331,#332,#333,#334,#335,#336,#337,#338,#339,#340,#341,#342,#343,
#344,#345,#346,#347,#348,#349,#350,#351,#352,#353,#354,#355,#356,#357,#358,#359,#360,#361,#362,
#363,#364,#365,#366,#367,#368,#369,#370,#371,#372,#373,#374,#375,#376,#377,#378,#379,#380,#381,
#382,#383,#384,#385,#386,#387,#388,#389,#390,#391,#392,#393,#394,#395,#396,#397,#398,#399,#400,
#401,#402,#403,#404,#405,#406,#407,#408,#409,#410,#411,#412,#413,#414,#415,#416,#417,#418,#419,
#420,#421,#422,#423,#424,#425,#426,#427,#428,#429,#430,#431,#432,#433,#434,#435,#436,#437,#438),
.UNSPECIFIED.,.F.,.F.,(4,1,1,1,1,1,1,1,1,1,1,1,1,1,1,1,1,1,1,1,1,1,1,1,1,1,1,1,1,1,1,1,1,1,1,1,
1,1,1,1,1,1,1,1,1,1,1,1,1,1,1,1,1,1,1,1,1,1,1,1,1,1,1,1,1,1,1,1,1,1,1,1,1,1,1,1,1,1,1,1,1,1,1,1,
1,1,1,1,1,1,1,1,1,1,1,1,1,1,1,1,1,1,1,1,1,1,1,1,1,1,1,1,1,1,1,1,1,1,1,1,1,1,4),(0.,
0.00911260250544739,0.0161929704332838,0.0264618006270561,0.0349037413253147,0.0381825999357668,
0.0439502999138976,0.0480113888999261,0.0530894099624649,0.0595182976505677,0.0661056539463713,
0.0760047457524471,0.0845112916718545,0.0908845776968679,0.0984438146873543,0.10471855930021,
0.109811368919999,0.114385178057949,0.118526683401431,0.123643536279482,0.129337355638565,
0.137682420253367,0.149649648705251,0.162400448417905,0.173127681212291,0.183434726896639,
0.192644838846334,0.200399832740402,0.213302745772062,0.22420092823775,0.22822949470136,
0.231894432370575,0.236368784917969,0.241437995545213,0.246241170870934,0.2506628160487,
0.257607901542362,0.27139243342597,0.279833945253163,0.289319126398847,0.296867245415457,
0.303563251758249,0.310550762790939,0.316760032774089,0.323034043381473,0.330163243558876,
0.338593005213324,0.340496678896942,0.349199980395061,0.358361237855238,0.372914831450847,
0.392419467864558,0.407971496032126,0.413164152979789,0.417787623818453,0.422549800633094,
0.428600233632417,0.434591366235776,0.440686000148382,0.447359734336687,0.457792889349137,
0.470098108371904,0.477386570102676,0.484879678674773,0.491898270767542,0.499019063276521,
0.507932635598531,0.513418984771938,0.518534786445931,0.528117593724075,0.539945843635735,
0.553903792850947,0.566829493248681,0.576428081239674,0.587658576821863,0.600334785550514,
0.60858936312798,0.617771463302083,0.623188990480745,0.629789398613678,0.63686822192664,
0.645094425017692,0.655074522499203,0.664438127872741,0.673137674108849,0.680544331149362,
0.690087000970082,0.697304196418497,0.703900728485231,0.709654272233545,0.71429887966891,
0.718725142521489,0.722892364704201,0.727373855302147,0.730710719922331,0.737407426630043,
0.74749199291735,0.760161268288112,0.770493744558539,0.78263618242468,0.793776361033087,
0.808689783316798,0.822575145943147,0.829909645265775,0.835126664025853,0.838756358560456,
0.844903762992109,0.851383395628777,0.857103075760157,0.862081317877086,0.870568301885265,
0.88069992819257,0.895362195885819,0.903753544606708,0.912686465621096,0.921282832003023,
0.927959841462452,0.934684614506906,0.941611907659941,0.947843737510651,0.9564907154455,
0.970838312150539,1.),.UNSPECIFIED.);
#440=DIRECTION('',(0.,0.,1.));
#441=VECTOR('',#440,1.);
#442=SURFACE_OF_LINEAR_EXTRUSION('',#439,#441);
#443=CARTESIAN_POINT('',(-346.614016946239,177.25293926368,20.));
#444=CARTESIAN_POINT('',(-342.258832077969,176.736071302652,20.));
#445=CARTESIAN_POINT('',(-334.630281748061,175.39162503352,20.));
#446=CARTESIAN_POINT('',(-322.207300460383,172.127174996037,20.));
#447=CARTESIAN_POINT('',(-310.217613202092,171.698509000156,20.));
#448=CARTESIAN_POINT('',(-298.545158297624,170.093475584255,20.));
#449=CARTESIAN_POINT('',(-292.347039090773,176.459047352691,20.));
#450=CARTESIAN_POINT('',(-291.182342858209,183.091468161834,20.));
#451=CARTESIAN_POINT('',(-293.102487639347,190.125199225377,20.));
#452=CARTESIAN_POINT('',(-298.136160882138,196.044180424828,20.));
#453=CARTESIAN_POINT('',(-298.244257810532,205.192484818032,20.));
#454=CARTESIAN_POINT('',(-295.736411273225,216.192904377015,20.));
#455=CARTESIAN_POINT('',(-284.569633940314,223.791693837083,20.));
#456=CARTESIAN_POINT('',(-272.468924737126,223.790848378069,20.));
#457=CARTESIAN_POINT('',(-261.822732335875,221.83725535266,20.));
#458=CARTESIAN_POINT('',(-253.508338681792,215.027886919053,20.));
#459=CARTESIAN_POINT('',(-252.519805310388,205.637670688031,20.));
#460=CARTESIAN_POINT('',(-253.401239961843,197.704569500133,20.));
#461=CARTESIAN_POINT('',(-258.083644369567,192.838143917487,20.));
#462=CARTESIAN_POINT('',(-261.982487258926,187.038073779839,20.));
#463=CARTESIAN_POINT('',(-259.723590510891,179.281829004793,20.));
#464=CARTESIAN_POINT('',(-251.85351516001,173.410794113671,20.));
#465=CARTESIAN_POINT('',(-238.882669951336,174.366863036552,20.));
#466=CARTESIAN_POINT('',(-223.106306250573,172.916178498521,20.));
#467=CARTESIAN_POINT('',(-206.446351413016,177.519441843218,20.));
#468=CARTESIAN_POINT('',(-190.340722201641,179.324744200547,20.));
#469=CARTESIAN_POINT('',(-176.104340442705,182.349104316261,20.));
#470=CARTESIAN_POINT('',(-163.084589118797,183.756571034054,20.));
#471=CARTESIAN_POINT('',(-148.792468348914,185.344350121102,20.));
#472=CARTESIAN_POINT('',(-133.845084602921,186.050988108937,20.));
#473=CARTESIAN_POINT('',(-120.037545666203,188.092783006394,20.));
#474=CARTESIAN_POINT('',(-111.803418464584,182.78300514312,20.));
#475=CARTESIAN_POINT('',(-111.114798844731,176.517531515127,20.));
#476=CARTESIAN_POINT('',(-112.872183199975,170.302712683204,20.));
#477=CARTESIAN_POINT('',(-117.51230307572,165.00187907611,20.));
#478=CARTESIAN_POINT('',(-123.315488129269,161.011850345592,20.));
#479=CARTESIAN_POINT('',(-125.896005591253,153.215627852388,20.));
#480=CARTESIAN_POINT('',(-123.567507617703,140.925485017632,20.));
#481=CARTESIAN_POINT('',(-111.885113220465,130.083380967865,20.));
#482=CARTESIAN_POINT('',(-95.9373878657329,129.405548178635,20.));
#483=CARTESIAN_POINT('',(-84.8374492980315,134.872773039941,20.));
#484=CARTESIAN_POINT('',(-75.3086923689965,142.091043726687,20.));
#485=CARTESIAN_POINT('',(-72.69488446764,152.131847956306,20.));
#486=CARTESIAN_POINT('',(-71.682221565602,162.525177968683,20.));
#487=CARTESIAN_POINT('',(-78.7549399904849,168.95980357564,20.));
#488=CARTESIAN_POINT('',(-85.5168727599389,177.593918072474,20.));
#489=CARTESIAN_POINT('',(-75.9954684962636,187.469530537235,20.));
#490=CARTESIAN_POINT('',(-67.465440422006,186.249883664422,20.));
#491=CARTESIAN_POINT('',(-58.2366685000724,186.245624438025,20.));
#492=CARTESIAN_POINT('',(-48.8132938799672,186.807289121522,20.));
#493=CARTESIAN_POINT('',(-33.2056867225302,186.136328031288,20.));
#494=CARTESIAN_POINT('',(-12.537524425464,187.517682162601,20.));
#495=CARTESIAN_POINT('',(11.5103154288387,188.924750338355,20.));
#496=CARTESIAN_POINT('',(30.1849441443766,189.011039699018,20.));
#497=CARTESIAN_POINT('',(43.274525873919,189.889723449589,20.));
#498=CARTESIAN_POINT('',(48.0164168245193,183.93060080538,20.));
#499=CARTESIAN_POINT('',(50.5774279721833,176.61864331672,20.));
#500=CARTESIAN_POINT('',(46.6862848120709,168.851584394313,20.));
#501=CARTESIAN_POINT('',(40.9041593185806,162.199492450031,20.));
#502=CARTESIAN_POINT('',(40.64695704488,152.479125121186,20.));
#503=CARTESIAN_POINT('',(45.9753197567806,142.379370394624,20.));
#504=CARTESIAN_POINT('',(57.8656738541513,133.606511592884,20.));
#505=CARTESIAN_POINT('',(73.1959810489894,132.323999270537,20.));
#506=CARTESIAN_POINT('',(85.4204286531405,138.139947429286,20.));
#507=CARTESIAN_POINT('',(91.293500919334,147.271529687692,20.));
#508=CARTESIAN_POINT('',(92.5730258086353,158.4481335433,20.));
#509=CARTESIAN_POINT('',(85.6844462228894,167.316232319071,20.));
#510=CARTESIAN_POINT('',(79.232667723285,177.018523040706,20.));
#511=CARTESIAN_POINT('',(84.0194361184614,186.167590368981,20.));
#512=CARTESIAN_POINT('',(92.1790662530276,191.943337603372,20.));
#513=CARTESIAN_POINT('',(105.569170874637,191.361104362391,20.));
#514=CARTESIAN_POINT('',(122.280046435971,190.653524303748,20.));
#515=CARTESIAN_POINT('',(140.914243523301,189.654608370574,20.));
#516=CARTESIAN_POINT('',(158.454428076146,188.894575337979,20.));
#517=CARTESIAN_POINT('',(174.308585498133,185.327210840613,20.));
#518=CARTESIAN_POINT('',(190.189391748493,182.787078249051,20.));
#519=CARTESIAN_POINT('',(205.520873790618,180.707698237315,20.));
#520=CARTESIAN_POINT('',(219.985633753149,180.329082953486,20.));
#521=CARTESIAN_POINT('',(230.995486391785,184.637134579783,20.));
#522=CARTESIAN_POINT('',(236.389631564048,193.96740057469,20.));
#523=CARTESIAN_POINT('',(234.339311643,204.099038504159,20.));
#524=CARTESIAN_POINT('',(225.306966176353,209.962524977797,20.));
#525=CARTESIAN_POINT('',(217.656290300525,220.555550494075,20.));
#526=CARTESIAN_POINT('',(221.434208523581,234.75430994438,20.));
#527=CARTESIAN_POINT('',(231.413638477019,244.865362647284,20.));
#528=CARTESIAN_POINT('',(243.993390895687,246.564716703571,20.));
#529=CARTESIAN_POINT('',(256.397546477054,246.182971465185,20.));
#530=CARTESIAN_POINT('',(266.945867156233,239.095387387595,20.));
#531=CARTESIAN_POINT('',(270.91124628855,228.240855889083,20.));
#532=CARTESIAN_POINT('',(271.900091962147,218.911541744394,20.));
#533=CARTESIAN_POINT('',(269.383381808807,210.410798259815,20.));
#534=CARTESIAN_POINT('',(262.973596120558,206.796374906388,20.));
#535=CARTESIAN_POINT('',(257.405320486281,203.494234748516,20.));
#536=CARTESIAN_POINT('',(254.366674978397,197.840465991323,20.));
#537=CARTESIAN_POINT('',(253.039843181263,191.819395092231,20.));
#538=CARTESIAN_POINT('',(256.984226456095,185.562553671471,20.));
#539=CARTESIAN_POINT('',(265.893667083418,181.084683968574,20.));
#540=CARTESIAN_POINT('',(279.937105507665,178.460081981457,20.));
#541=CARTESIAN_POINT('',(295.857197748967,180.090608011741,20.));
#542=CARTESIAN_POINT('',(312.651995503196,181.441283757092,20.));
#543=CARTESIAN_POINT('',(328.737066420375,183.00567531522,20.));
#544=CARTESIAN_POINT('',(346.881588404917,185.540652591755,20.));
#545=CARTESIAN_POINT('',(366.113245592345,187.229469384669,20.));
#546=CARTESIAN_POINT('',(383.091271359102,188.04749837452,20.));
#547=CARTESIAN_POINT('',(396.458935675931,188.664584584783,20.));
#548=CARTESIAN_POINT('',(402.675626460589,183.140178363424,20.));
#549=CARTESIAN_POINT('',(405.39161009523,176.05770043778,20.));
#550=CARTESIAN_POINT('',(401.505929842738,168.451181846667,20.));
#551=CARTESIAN_POINT('',(396.461764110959,161.551049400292,20.));
#552=CARTESIAN_POINT('',(390.92163398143,155.05556636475,20.));
#553=CARTESIAN_POINT('',(389.792834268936,145.579550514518,20.));
#554=CARTESIAN_POINT('',(394.021335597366,134.09834255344,20.));
#555=CARTESIAN_POINT('',(409.134243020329,126.516671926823,20.));
#556=CARTESIAN_POINT('',(426.048788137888,125.694722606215,20.));
#557=CARTESIAN_POINT('',(439.554422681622,133.604839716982,20.));
#558=CARTESIAN_POINT('',(447.862161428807,144.021049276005,20.));
#559=CARTESIAN_POINT('',(446.55931165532,156.434302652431,20.));
#560=CARTESIAN_POINT('',(440.954543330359,165.911582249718,20.));
#561=CARTESIAN_POINT('',(431.825738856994,170.072611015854,20.));
#562=CARTESIAN_POINT('',(428.260955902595,181.518173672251,20.));
#563=CARTESIAN_POINT('',(438.266894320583,188.341732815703,20.));
#564=CARTESIAN_POINT('',(452.042143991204,189.873820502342,20.));
#565=CARTESIAN_POINT('',(477.265793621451,189.952490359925,20.));
#566=CARTESIAN_POINT('',(497.972189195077,187.546114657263,20.));
#567=CARTESIAN_POINT('',(512.,187.076538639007,20.));
#568=B_SPLINE_CURVE_WITH_KNOTS('',3,(#443,#444,#445,#446,#447,#448,#449,#450,#451,#452,#453,
#454,#455,#456,#457,#458,#459,#460,#461,#462,#463,#464,#465,#466,#467,#468,#469,#470,#471,#472,
#473,#474,#475,#476,#477,#478,#479,#480,#481,#482,#483,#484,#485,#486,#487,#488,#489,#490,#491,
#492,#493,#494,#495,#496,#497,#498,#499,#500,#501,#502,#503,#504,#505,#506,#507,#508,#509,#510,
#511,#512,#513,#514,#515,#516,#517,#518,#519,#520,#521,#522,#523,#524,#525,#526,#527,#528,#529,
#530,#531,#532,#533,#534,#535,#536,#537,#538,#539,#540,#541,#542,#543,#544,#545,#546,#547,#548,
#549,#550,#551,#552,#553,#554,#555,#556,#557,#558,#559,#560,#561,#562,#563,#564,#565,#566,#567),
.UNSPECIFIED.,.F.,.F.,(4,1,1,1,1,1,1,1,1,1,1,1,1,1,1,1,1,1,1,1,1,1,1,1,1,1,1,1,1,1,1,1,1,1,1,1,
1,1,1,1,1,1,1,1,1,1,1,1,1,1,1,1,1,1,1,1,1,1,1,1,1,1,1,1,1,1,1,1,1,1,1,1,1,1,1,1,1,1,1,1,1,1,1,1,
1,1,1,1,1,1,1,1,1,1,1,1,1,1,1,1,1,1,1,1,1,1,1,1,1,1,1,1,1,1,1,1,1,1,1,1,1,1,4),(0.,
0.00911260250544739,0.0161929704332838,0.0264618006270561,0.0349037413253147,0.0381825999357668,
0.0439502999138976,0.0480113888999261,0.0530894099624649,0.0595182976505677,0.0661056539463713,
0.0760047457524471,0.0845112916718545,0.0908845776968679,0.0984438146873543,0.10471855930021,
0.109811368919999,0.114385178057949,0.118526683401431,0.123643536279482,0.129337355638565,
0.137682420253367,0.149649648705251,0.162400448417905,0.173127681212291,0.183434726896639,
0.192644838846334,0.200399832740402,0.213302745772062,0.22420092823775,0.22822949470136,
0.231894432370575,0.236368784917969,0.241437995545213,0.246241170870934,0.2506628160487,
0.257607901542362,0.27139243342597,0.279833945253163,0.289319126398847,0.296867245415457,
0.303563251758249,0.310550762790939,0.316760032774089,0.323034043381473,0.330163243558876,
0.338593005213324,0.340496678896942,0.349199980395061,0.358361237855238,0.372914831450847,
0.392419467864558,0.407971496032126,0.413164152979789,0.417787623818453,0.422549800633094,
0.428600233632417,0.434591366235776,0.440686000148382,0.447359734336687,0.457792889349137,
0.470098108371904,0.477386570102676,0.484879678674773,0.491898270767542,0.499019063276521,
0.507932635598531,0.513418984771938,0.518534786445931,0.528117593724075,0.539945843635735,
0.553903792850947,0.566829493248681,0.576428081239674,0.587658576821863,0.600334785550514,
0.60858936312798,0.617771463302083,0.623188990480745,0.629789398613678,0.63686822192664,
0.645094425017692,0.655074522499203,0.664438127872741,0.673137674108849,0.680544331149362,
0.690087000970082,0.697304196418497,0.703900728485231,0.709654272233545,0.71429887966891,
0.718725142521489,0.722892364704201,0.727373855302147,0.730710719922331,0.737407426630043,
0.74749199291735,0.760161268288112,0.770493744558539,0.78263618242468,0.793776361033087,
0.808689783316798,0.822575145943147,0.829909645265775,0.835126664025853,0.838756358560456,
0.844903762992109,0.851383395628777,0.857103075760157,0.862081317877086,0.870568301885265,
0.88069992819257,0.895362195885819,0.903753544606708,0.912686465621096,0.921282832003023,
0.927959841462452,0.934684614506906,0.941611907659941,0.947843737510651,0.9564907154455,
0.970838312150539,1.),.UNSPECIFIED.);
#569=EDGE_CURVE('E59',#102,#286,#568,.T.);
#570=ORIENTED_EDGE('',*,*,#569,.F.);
#571=ORIENTED_EDGE('',*,*,#105,.T.);
#572=CARTESIAN_POINT('',(-346.614016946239,177.25293926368,0.));
#573=CARTESIAN_POINT('',(-342.258832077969,176.736071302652,0.));
#574=CARTESIAN_POINT('',(-334.630281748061,175.39162503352,0.));
#575=CARTESIAN_POINT('',(-322.207300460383,172.127174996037,0.));
#576=CARTESIAN_POINT('',(-310.217613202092,171.698509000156,0.));
#577=CARTESIAN_POINT('',(-298.545158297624,170.093475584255,0.));
#578=CARTESIAN_POINT('',(-292.347039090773,176.459047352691,0.));
#579=CARTESIAN_POINT('',(-291.182342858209,183.091468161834,0.));
#580=CARTESIAN_POINT('',(-293.102487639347,190.125199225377,0.));
#581=CARTESIAN_POINT('',(-298.136160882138,196.044180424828,0.));
#582=CARTESIAN_POINT('',(-298.244257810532,205.192484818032,0.));
#583=CARTESIAN_POINT('',(-295.736411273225,216.192904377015,0.));
#584=CARTESIAN_POINT('',(-284.569633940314,223.791693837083,0.));
#585=CARTESIAN_POINT('',(-272.468924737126,223.790848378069,0.));
#586=CARTESIAN_POINT('',(-261.822732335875,221.83725535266,0.));
#587=CARTESIAN_POINT('',(-253.508338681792,215.027886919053,0.));
#588=CARTESIAN_POINT('',(-252.519805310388,205.637670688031,0.));
#589=CARTESIAN_POINT('',(-253.401239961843,197.704569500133,0.));
#590=CARTESIAN_POINT('',(-258.083644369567,192.838143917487,0.));
#591=CARTESIAN_POINT('',(-261.982487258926,187.038073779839,0.));
#592=CARTESIAN_POINT('',(-259.723590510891,179.281829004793,0.));
#593=CARTESIAN_POINT('',(-251.85351516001,173.410794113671,0.));
#594=CARTESIAN_POINT('',(-238.882669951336,174.366863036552,0.));
#595=CARTESIAN_POINT('',(-223.106306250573,172.916178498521,0.));
#596=CARTESIAN_POINT('',(-206.446351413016,177.519441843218,0.));
#597=CARTESIAN_POINT('',(-190.340722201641,179.324744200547,0.));
#598=CARTESIAN_POINT('',(-176.104340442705,182.349104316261,0.));
#599=CARTESIAN_POINT('',(-163.084589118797,183.756571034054,0.));
#600=CARTESIAN_POINT('',(-148.792468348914,185.344350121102,0.));
#601=CARTESIAN_POINT('',(-133.845084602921,186.050988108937,0.));
#602=CARTESIAN_POINT('',(-120.037545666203,188.092783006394,0.));
#603=CARTESIAN_POINT('',(-111.803418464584,182.78300514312,0.));
#604=CARTESIAN_POINT('',(-111.114798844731,176.517531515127,0.));
#605=CARTESIAN_POINT('',(-112.872183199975,170.302712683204,0.));
#606=CARTESIAN_POINT('',(-117.51230307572,165.00187907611,0.));
#607=CARTESIAN_POINT('',(-123.315488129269,161.011850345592,0.));
#608=CARTESIAN_POINT('',(-125.896005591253,153.215627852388,0.));
#609=CARTESIAN_POINT('',(-123.567507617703,140.925485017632,0.));
#610=CARTESIAN_POINT('',(-111.885113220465,130.083380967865,0.));
#611=CARTESIAN_POINT('',(-95.9373878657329,129.405548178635,0.));
#612=CARTESIAN_POINT('',(-84.8374492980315,134.872773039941,0.));
#613=CARTESIAN_POINT('',(-75.3086923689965,142.091043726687,0.));
#614=CARTESIAN_POINT('',(-72.69488446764,152.131847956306,0.));
#615=CARTESIAN_POINT('',(-71.682221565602,162.525177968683,0.));
#616=CARTESIAN_POINT('',(-78.7549399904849,168.95980357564,0.));
#617=CARTESIAN_POINT('',(-85.5168727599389,177.593918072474,0.));
#618=CARTESIAN_POINT('',(-75.9954684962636,187.469530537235,0.));
#619=CARTESIAN_POINT('',(-67.465440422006,186.249883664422,0.));
#620=CARTESIAN_POINT('',(-58.2366685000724,186.245624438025,0.));
#621=CARTESIAN_POINT('',(-48.8132938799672,186.807289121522,0.));
#622=CARTESIAN_POINT('',(-33.2056867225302,186.136328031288,0.));
#623=CARTESIAN_POINT('',(-12.537524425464,187.517682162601,0.));
#624=CARTESIAN_POINT('',(11.5103154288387,188.924750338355,0.));
#625=CARTESIAN_POINT('',(30.1849441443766,189.011039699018,0.));
#626=CARTESIAN_POINT('',(43.274525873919,189.889723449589,0.));
#627=CARTESIAN_POINT('',(48.0164168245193,183.93060080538,0.));
#628=CARTESIAN_POINT('',(50.5774279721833,176.61864331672,0.));
#629=CARTESIAN_POINT('',(46.6862848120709,168.851584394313,0.));
#630=CARTESIAN_POINT('',(40.9041593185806,162.199492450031,0.));
#631=CARTESIAN_POINT('',(40.64695704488,152.479125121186,0.));
#632=CARTESIAN_POINT('',(45.9753197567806,142.379370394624,0.));
#633=CARTESIAN_POINT('',(57.8656738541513,133.606511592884,0.));
#634=CARTESIAN_POINT('',(73.1959810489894,132.323999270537,0.));
#635=CARTESIAN_POINT('',(85.4204286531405,138.139947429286,0.));
#636=CARTESIAN_POINT('',(91.293500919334,147.271529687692,0.));
#637=CARTESIAN_POINT('',(92.5730258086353,158.4481335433,0.));
#638=CARTESIAN_POINT('',(85.6844462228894,167.316232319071,0.));
#639=CARTESIAN_POINT('',(79.232667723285,177.018523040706,0.));
#640=CARTESIAN_POINT('',(84.0194361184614,186.167590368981,0.));
#641=CARTESIAN_POINT('',(92.1790662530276,191.943337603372,0.));
#642=CARTESIAN_POINT('',(105.569170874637,191.361104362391,0.));
#643=CARTESIAN_POINT('',(122.280046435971,190.653524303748,0.));
#644=CARTESIAN_POINT('',(140.914243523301,189.654608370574,0.));
#645=CARTESIAN_POINT('',(158.454428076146,188.894575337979,0.));
#646=CARTESIAN_POINT('',(174.308585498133,185.327210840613,0.));
#647=CARTESIAN_POINT('',(190.189391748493,182.787078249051,0.));
#648=CARTESIAN_POINT('',(205.520873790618,180.707698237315,0.));
#649=CARTESIAN_POINT('',(219.985633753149,180.329082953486,0.));
#650=CARTESIAN_POINT('',(230.995486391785,184.637134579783,0.));
#651=CARTESIAN_POINT('',(236.389631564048,193.96740057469,0.));
#652=CARTESIAN_POINT('',(234.339311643,204.099038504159,0.));
#653=CARTESIAN_POINT('',(225.306966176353,209.962524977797,0.));
#654=CARTESIAN_POINT('',(217.656290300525,220.555550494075,0.));
#655=CARTESIAN_POINT('',(221.434208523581,234.75430994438,0.));
#656=CARTESIAN_POINT('',(231.413638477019,244.865362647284,0.));
#657=CARTESIAN_POINT('',(243.993390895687,246.564716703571,0.));
#658=CARTESIAN_POINT('',(256.397546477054,246.182971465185,0.));
#659=CARTESIAN_POINT('',(266.945867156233,239.095387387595,0.));
#660=CARTESIAN_POINT('',(270.91124628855,228.240855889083,0.));
#661=CARTESIAN_POINT('',(271.900091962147,218.911541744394,0.));
#662=CARTESIAN_POINT('',(269.383381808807,210.410798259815,0.));
#663=CARTESIAN_POINT('',(262.973596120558,206.796374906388,0.));
#664=CARTESIAN_POINT('',(257.405320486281,203.494234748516,0.));
#665=CARTESIAN_POINT('',(254.366674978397,197.840465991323,0.));
#666=CARTESIAN_POINT('',(253.039843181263,191.819395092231,0.));
#667=CARTESIAN_POINT('',(256.984226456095,185.562553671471,0.));
#668=CARTESIAN_POINT('',(265.893667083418,181.084683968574,0.));
#669=CARTESIAN_POINT('',(279.937105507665,178.460081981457,0.));
#670=CARTESIAN_POINT('',(295.857197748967,180.090608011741,0.));
#671=CARTESIAN_POINT('',(312.651995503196,181.441283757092,0.));
#672=CARTESIAN_POINT('',(328.737066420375,183.00567531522,0.));
#673=CARTESIAN_POINT('',(346.881588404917,185.540652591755,0.));
#674=CARTESIAN_POINT('',(366.113245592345,187.229469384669,0.));
#675=CARTESIAN_POINT('',(383.091271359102,188.04749837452,0.));
#676=CARTESIAN_POINT('',(396.458935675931,188.664584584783,0.));
#677=CARTESIAN_POINT('',(402.675626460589,183.140178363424,0.));
#678=CARTESIAN_POINT('',(405.39161009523,176.05770043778,0.));
#679=CARTESIAN_POINT('',(401.505929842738,168.451181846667,0.));
#680=CARTESIAN_POINT('',(396.461764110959,161.551049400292,0.));
#681=CARTESIAN_POINT('',(390.92163398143,155.05556636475,0.));
#682=CARTESIAN_POINT('',(389.792834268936,145.579550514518,0.));
#683=CARTESIAN_POINT('',(394.021335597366,134.09834255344,0.));
#684=CARTESIAN_POINT('',(409.134243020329,126.516671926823,0.));
#685=CARTESIAN_POINT('',(426.048788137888,125.694722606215,0.));
#686=CARTESIAN_POINT('',(439.554422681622,133.604839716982,0.));
#687=CARTESIAN_POINT('',(447.862161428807,144.021049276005,0.));
#688=CARTESIAN_POINT('',(446.55931165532,156.434302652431,0.));
#689=CARTESIAN_POINT('',(440.954543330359,165.911582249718,0.));
#690=CARTESIAN_POINT('',(431.825738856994,170.072611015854,0.));
#691=CARTESIAN_POINT('',(428.260955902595,181.518173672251,0.));
#692=CARTESIAN_POINT('',(438.266894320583,188.341732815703,0.));
#693=CARTESIAN_POINT('',(452.042143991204,189.873820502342,0.));
#694=CARTESIAN_POINT('',(477.265793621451,189.952490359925,0.));
#695=CARTESIAN_POINT('',(497.972189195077,187.546114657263,0.));
#696=CARTESIAN_POINT('',(512.,187.076538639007,0.));
#697=B_SPLINE_CURVE_WITH_KNOTS('',3,(#572,#573,#574,#575,#576,#577,#578,#579,#580,#581,#582,
#583,#584,#585,#586,#587,#588,#589,#590,#591,#592,#593,#594,#595,#596,#597,#598,#599,#600,#601,
#602,#603,#604,#605,#606,#607,#608,#609,#610,#611,#612,#613,#614,#615,#616,#617,#618,#619,#620,
#621,#622,#623,#624,#625,#626,#627,#628,#629,#630,#631,#632,#633,#634,#635,#636,#637,#638,#639,
#640,#641,#642,#643,#644,#645,#646,#647,#648,#649,#650,#651,#652,#653,#654,#655,#656,#657,#658,
#659,#660,#661,#662,#663,#664,#665,#666,#667,#668,#669,#670,#671,#672,#673,#674,#675,#676,#677,
#678,#679,#680,#681,#682,#683,#684,#685,#686,#687,#688,#689,#690,#691,#692,#693,#694,#695,#696),
.UNSPECIFIED.,.F.,.F.,(4,1,1,1,1,1,1,1,1,1,1,1,1,1,1,1,1,1,1,1,1,1,1,1,1,1,1,1,1,1,1,1,1,1,1,1,
1,1,1,1,1,1,1,1,1,1,1,1,1,1,1,1,1,1,1,1,1,1,1,1,1,1,1,1,1,1,1,1,1,1,1,1,1,1,1,1,1,1,1,1,1,1,1,1,
1,1,1,1,1,1,1,1,1,1,1,1,1,1,1,1,1,1,1,1,1,1,1,1,1,1,1,1,1,1,1,1,1,1,1,1,1,1,4),(0.,
0.00911260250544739,0.0161929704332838,0.0264618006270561,0.0349037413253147,0.0381825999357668,
0.0439502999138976,0.0480113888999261,0.0530894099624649,0.0595182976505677,0.0661056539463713,
0.0760047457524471,0.0845112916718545,0.0908845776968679,0.0984438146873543,0.10471855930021,
0.109811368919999,0.114385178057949,0.118526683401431,0.123643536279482,0.129337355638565,
0.137682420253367,0.149649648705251,0.162400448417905,0.173127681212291,0.183434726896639,
0.192644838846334,0.200399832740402,0.213302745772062,0.22420092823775,0.22822949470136,
0.231894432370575,0.236368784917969,0.241437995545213,0.246241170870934,0.2506628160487,
0.257607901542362,0.27139243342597,0.279833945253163,0.289319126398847,0.296867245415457,
0.303563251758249,0.310550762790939,0.316760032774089,0.323034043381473,0.330163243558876,
0.338593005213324,0.340496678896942,0.349199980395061,0.358361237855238,0.372914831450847,
0.392419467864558,0.407971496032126,0.413164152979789,0.417787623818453,0.422549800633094,
0.428600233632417,0.434591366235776,0.440686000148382,0.447359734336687,0.457792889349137,
0.470098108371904,0.477386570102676,0.484879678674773,0.491898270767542,0.499019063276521,
0.507932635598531,0.513418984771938,0.518534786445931,0.528117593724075,0.539945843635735,
0.553903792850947,0.566829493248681,0.576428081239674,0.587658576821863,0.600334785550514,
0.60858936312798,0.617771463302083,0.623188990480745,0.629789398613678,0.63686822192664,
0.645094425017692,0.655074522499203,0.664438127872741,0.673137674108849,0.680544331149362,
0.690087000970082,0.697304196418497,0.703900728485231,0.709654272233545,0.71429887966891,
0.718725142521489,0.722892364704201,0.727373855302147,0.730710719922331,0.737407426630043,
0.74749199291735,0.760161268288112,0.770493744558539,0.78263618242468,0.793776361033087,
0.808689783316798,0.822575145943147,0.829909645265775,0.835126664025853,0.838756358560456,
0.844903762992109,0.851383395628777,0.857103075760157,0.862081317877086,0.870568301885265,
0.88069992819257,0.895362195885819,0.903753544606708,0.912686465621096,0.921282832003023,
0.927959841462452,0.934684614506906,0.941611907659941,0.947843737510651,0.9564907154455,
0.970838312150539,1.),.UNSPECIFIED.);
#698=EDGE_CURVE('E11',#104,#284,#697,.T.);
#699=ORIENTED_EDGE('',*,*,#698,.T.);
#700=ORIENTED_EDGE('',*,*,#287,.T.);
#701=EDGE_LOOP('',(#570,#571,#699,#700));
#702=FACE_BOUND('',#701,.T.);
#703=ADVANCED_FACE('F127',(#702),#442,.T.);
#704=CARTESIAN_POINT('',(512.,356.,20.));
#705=DIRECTION('',(0.,-1.,0.));
#706=DIRECTION('',(1.,0.,0.));
#707=AXIS2_PLACEMENT_3D('',#704,#705,#706);
#708=PLANE('',#707);
#709=ORIENTED_EDGE('',*,*,#192,.F.);
#710=DIRECTION('',(-1.,0.,0.));
#711=VECTOR('',#710,1.);
#712=CARTESIAN_POINT('',(512.,356.,20.));
#713=LINE('',#712,#711);
#714=EDGE_CURVE('E144',#302,#183,#713,.T.);
#715=ORIENTED_EDGE('',*,*,#714,.F.);
#716=ORIENTED_EDGE('',*,*,#303,.T.);
#717=DIRECTION('',(-1.,0.,0.));
#718=VECTOR('',#717,1.);
#719=CARTESIAN_POINT('',(512.,356.,0.));
#720=LINE('',#719,#718);
#721=EDGE_CURVE('E78',#294,#191,#720,.T.);
#722=ORIENTED_EDGE('',*,*,#721,.T.);
#723=EDGE_LOOP('',(#709,#715,#716,#722));
#724=FACE_BOUND('',#723,.T.);
#725=ADVANCED_FACE('F80',(#724),#708,.F.);
#726=CARTESIAN_POINT('',(0.,0.,20.));
#727=DIRECTION('',(0.,0.,1.));
#728=DIRECTION('',(1.,0.,0.));
#729=AXIS2_PLACEMENT_3D('',#726,#727,#728);
#730=PLANE('',#729);
#731=ORIENTED_EDGE('',*,*,#714,.T.);
#732=ORIENTED_EDGE('',*,*,#184,.T.);
#733=ORIENTED_EDGE('',*,*,#569,.T.);
#734=ORIENTED_EDGE('',*,*,#309,.T.);
#735=EDGE_LOOP('',(#731,#732,#733,#734));
#736=FACE_BOUND('',#735,.T.);
#737=ADVANCED_FACE('F131',(#736),#730,.T.);
#738=CARTESIAN_POINT('',(0.,0.,0.));
#739=DIRECTION('',(0.,0.,1.));
#740=DIRECTION('',(1.,0.,0.));
#741=AXIS2_PLACEMENT_3D('',#738,#739,#740);
#742=PLANE('',#741);
#743=ORIENTED_EDGE('',*,*,#269,.F.);
#744=ORIENTED_EDGE('',*,*,#721,.F.);
#745=ORIENTED_EDGE('',*,*,#295,.F.);
#746=ORIENTED_EDGE('',*,*,#698,.F.);
#747=EDGE_LOOP('',(#743,#744,#745,#746));
#748=FACE_BOUND('',#747,.T.);
#749=ADVANCED_FACE('F36',(#748),#742,.F.);
#750=CLOSED_SHELL('',(#273,#313,#703,#725,#737,#749));
#751=MANIFOLD_SOLID_BREP('B2',#750);
#752=ADVANCED_BREP_SHAPE_REPRESENTATION('',(#18,#751),#14);
#753=SHAPE_DEFINITION_REPRESENTATION(#9,#752);
ENDSEC;
END-ISO-10303-21;
